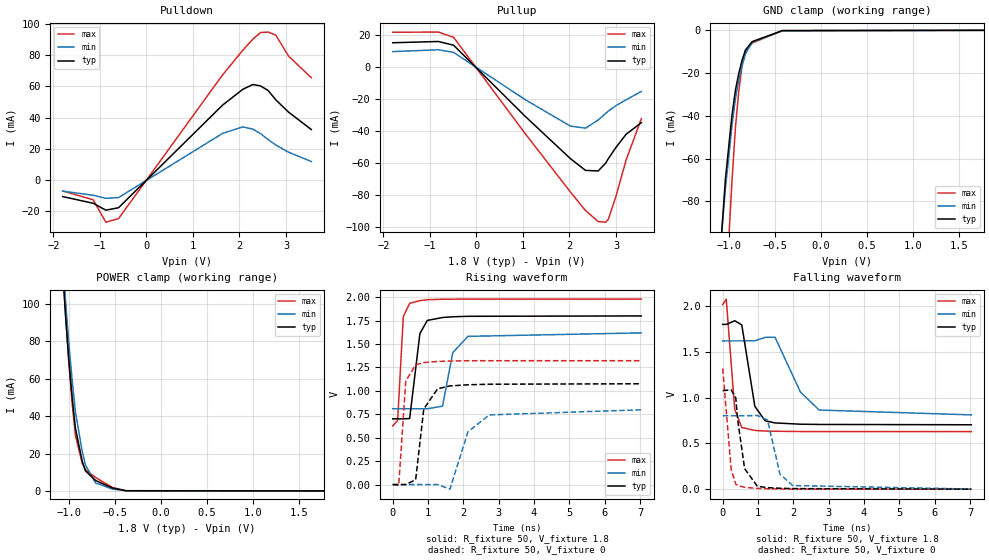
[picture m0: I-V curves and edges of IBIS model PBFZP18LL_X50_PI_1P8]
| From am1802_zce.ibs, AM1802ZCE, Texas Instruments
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|   Model Cell PBFZP18LL_X50_PI_1P8
|BC1833DV40CTPBFZ_PI_1P8
[Model]   PBFZP18LL_X50_PI_1P8
Model_type   I/O
Polarity   Non-Inverting
Enable   Active-Low
Vinl =  0.63
Vinh =  1.17
Cref =  15pF
Rref =  100.00M
Vref =  0V
Vmeas =  0.9
C_comp   2.232809p   2.073051p   2.295852p
[Model Spec]
Vinl   0.63   0.567   0.693
Vinh   1.17   1.053   1.287
[Temperature Range]   25   125   -40
[Voltage Range]   1.8   1.62   1.98
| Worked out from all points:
|   slope of the pulldown table from 0 to 0.27 V, typ, clamps not added: 31.4 ohm
|   slope of the pullup table from 0 to 0.27 V, typ, clamps not added: 33.4 ohm
|   GND clamp passes 1 mA (typ) near -0.54 V on its own axis
|   POWER clamp passes 1 mA (typ) near -0.49 V on its own axis
|   rising waveform, R_fixture 50, V_fixture 1.8: 20-80 % time 181ps typ, 267ps min, 105ps max; typ from 0.702 V to 1.8 V
|   rising waveform, R_fixture 50, V_fixture 0: 20-80 % time 233ps typ, 466ps min, 139ps max; typ from 0 V to 1.08 V
|   falling waveform, R_fixture 50, V_fixture 1.8: 20-80 % time 286ps typ, 636ps min, 163ps max; typ from 1.8 V to 0.704 V
|   falling waveform, R_fixture 50, V_fixture 0: 20-80 % time 222ps typ, 265ps min, 153ps max; typ from 1.08 V to 0 V
[POWER_clamp]
|   voltage   I(typ)   I(min)   I(max)
-1.8V     842.2mA    869.2mA    912.6mA
-1.073V   123.5mA    130.8mA    128.8mA
-1.036V   94.66mA    102.8mA    96.26mA
-1V       70.67mA    79.61mA    69.35mA
-963.6mV  50.26mA    59.42mA    47.15mA
-927.3mV  33.44mA    42.25mA    29.67mA
-854.5mV  15.93mA    21.22mA    14.83mA
-818.2mV  10.68mA    13.78mA    11.36mA
-709.1mV  5.588mA    4.293mA    7.178mA
-527.3mV  1.572mA    992uA      1.86mA
-381.8mV  113.5uA    102.1uA    81.29uA
1.764V    -883.6pA   -782.4nA   -251pA
[Pulldown]
|   voltage   I(typ)   I(min)   I(max)
-1.8V     -10.49mA   -6.992mA   -6.878mA
-1.145V   -14.77mA   -9.642mA   -12.54mA
-872.7mV  -19.17mA   -11.58mA   -26.88mA
-600mV    -17.64mA   -11.15mA   -24.61mA
1.636V    48.04mA    29.95mA    67.37mA
2.073V    58.21mA    34.18mA    83.2mA
2.291V    61.28mA    32.65mA    90.41mA
2.455V    60.33mA    29.78mA    94.55mA
2.618V    57.37mA    25.94mA    94.82mA
2.782V    51.43mA    22.55mA    92.84mA
3.055V    43.59mA    17.92mA    79.47mA
3.545V    32.43mA    11.97mA    65.61mA
[Pullup]
|   voltage   I(typ)   I(min)   I(max)
-1.8V     15.27mA    9.71mA     21.85mA
-818.2mV  16.05mA    10.88mA    21.94mA
-490.9mV  13.72mA    9.223mA    18.66mA
1.036V    -30.46mA   -20.11mA   -41.15mA
2.018V    -57.22mA   -36.91mA   -78.08mA
2.345V    -64.63mA   -38.19mA   -89.73mA
2.618V    -65.01mA   -33.11mA   -96.69mA
2.782V    -59.96mA   -28.87mA   -97.07mA
2.836V    -57.31mA   -27.51mA   -95.24mA
3V        -50.25mA   -24.09mA   -80.86mA
3.218V    -42.03mA   -20.43mA   -58.16mA
3.545V    -34.78mA   -15.26mA   -32.29mA
[GND_clamp]
|   voltage   I(typ)   I(min)   I(max)
-1.8V     -697.8mA   -553.2mA   -1.259A
-1.145V   -140.6mA   -131.7mA   -248.3mA
-1.109V   -115.1mA   -111.6mA   -203.3mA
-1.036V   -69.6mA    -74.06mA   -125.9mA
-963.6mV  -39.28mA   -44.17mA   -69.66mA
-927.3mV  -27.95mA   -31.85mA   -45.33mA
-890.9mV  -20.12mA   -23.33mA   -28.4mA
-854.5mV  -13.86mA   -16.38mA   -16.48mA
-818.2mV  -9.16mA    -11mA      -9.576mA
-745.5mV  -5.269mA   -5.602mA   -5.948mA
-418.2mV  -131.7uA   -213.2uA   -104.8uA
1.764V    17.23nA    526.4nA    24.82nA
[Ramp]
| variable   typ   min   max
dV/dt_f  0.7239307/0.2993504n  0.5357089/0.6657191n  0.8841936/0.1685277n
dV/dt_r   0.679758/0.2313607n  0.5131491/0.4715784n  0.8128359/0.1387347n
R_load = 50
[Rising Waveform]
R_fixture = 50
V_fixture = 1.8
V_fixture_min = 1.62
V_fixture_max = 1.98
|   time   V(typ)   V(min)   V(max)
0s        701.5mV    809.1mV    626.1mV
140ps     701.5mV    809.1mV    684.5mV
300ps     701.1mV    809.1mV    1.794V
480ps     705mV      809.1mV    1.934V
770ps     1.612V     809.1mV    1.964V
980ps     1.752V     809mV      1.973V
1.41ns    1.783V     836.4mV    1.978V
1.7ns     1.791V     1.407V     1.979V
2.13ns    1.796V     1.582V     1.98V
7.04ns    1.8V       1.619V     1.98V
[Rising Waveform]
R_fixture = 50
V_fixture = 0
V_fixture_min = 0
V_fixture_max = 0
|   time   V(typ)   V(min)   V(max)
0s        -1.101uV   -190.4nV   -628.2uV
170ps     -2.458uV   3.381uV    -8.727mV
370ps     -390.9uV   -15.37nV   1.104V
650ps     52.47mV    498.2nV    1.279V
880ps     807mV      12.96uV    1.302V
1.27ns    1.022V     43.68uV    1.314V
1.62ns    1.053V     -49.11mV   1.318V
2.13ns    1.065V     562.3mV    1.322V
2.73ns    1.071V     743.1mV    1.322V
7.04ns    1.076V     798.4mV    1.322V
[Falling Waveform]
R_fixture = 50
V_fixture = 1.8
V_fixture_min = 1.62
V_fixture_max = 1.98
|   time   V(typ)   V(min)   V(max)
0s        1.8V       1.62V      2.017V
100ps     1.8V       1.62V      2.077V
340ps     1.84V      1.62V      872.3mV
540ps     1.795V     1.62V      673.7mV
910ps     905mV      1.622V     641.8mV
1.2ns     747.8mV    1.658V     635.3mV
1.48ns    723.8mV    1.661V     632.5mV
2.2ns     709.7mV    1.061V     629.8mV
2.73ns    707.2mV    864.6mV    629.2mV
7.04ns    703.6mV    811.5mV    628.7mV
[Falling Waveform]
R_fixture = 50
V_fixture = 0
V_fixture_min = 0
V_fixture_max = 0
|   time   V(typ)   V(min)   V(max)
0s        1.076V     801.7mV    1.319V
240ps     1.085V     801.7mV    213.7mV
370ps     996.5mV    801.7mV    53.78mV
430ps     739.6mV    801.7mV    40.53mV
620ps     224.6mV    801.7mV    19.91mV
980ps     31.84mV    805.2mV    8.439mV
1.27ns    16.47mV    755.6mV    3.953mV
1.62ns    9.936mV    165.4mV    1.499mV
1.98ns    6.174mV    39.77mV    548.3uV
7.04ns    64.15uV    1.413mV    5.428uV
